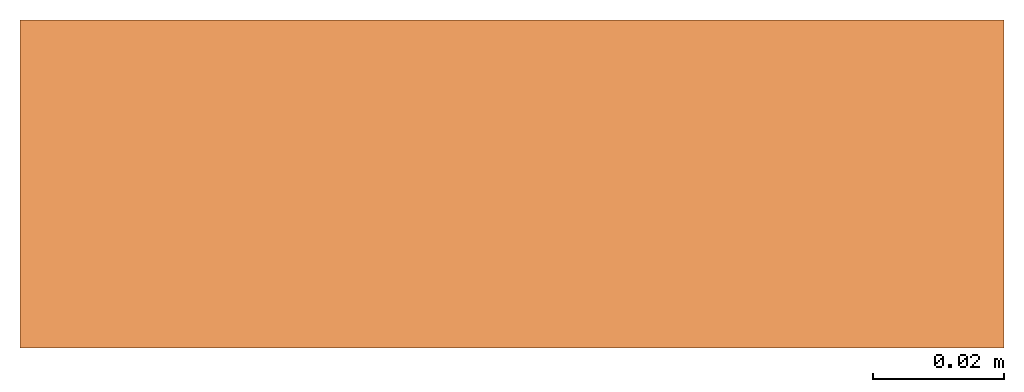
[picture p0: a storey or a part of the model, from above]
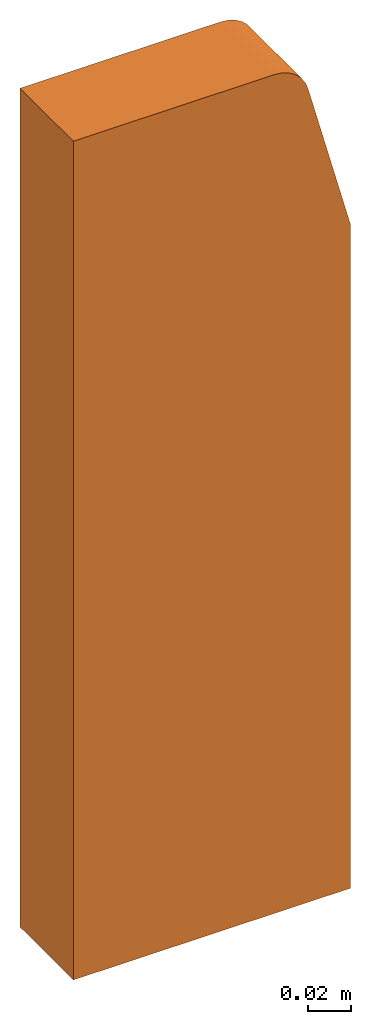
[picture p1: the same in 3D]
Properties of the parts of a building model (IFC2X3)

# File
Description: ViewDefinition [CoordinationView]
File name: 4938 - Closing end cap.ifc
Time: 2013-09-12T12:38:10
Written by: Autodesk Revit 2013
Made in: 20120221_2030(x64)

# IfcProject, Project Number
LongName: Project Name; Phase: Project Status

# IfcSite, Default
RefLatitude: 42, 21, 30, 344238; RefLongitude: -71, -3, -35, -194702; RefElevation: 0 mm

# IfcBuilding
Pset_BuildingCommon - NumberOfStoreys: 2
Other - Project Number: Project Number; Client Name: Owner; Project Address: Enter address here; Project Name: Project Name; Project Status: Project Status; Project Issue Date: Issue Date

# IfcBuildingStorey (2)
Constraints - Elevation Base: 0
Graphics - Symbol at End 1 Default: no; Symbol: M_Level Head - Circle: M_Level Head - Circle; Line Pattern: Center; Color: 0; Symbol at End 2 Default: yes; Line Weight: 1
Identity Data - Structural: no; Building Story: yes
Dimensions - Computation Height: 0 mm
Name | LongName = Name | Elevation (mm) = Constraints, Elevation (mm)
T.O. Fnd. Wall | T.O. Fnd. Wall | -300
Level 1 | Level 1 | 0

# IfcBuildingElementProxy: 4938 - Closing end cap, Civil-Drainage-Channel-ACO-KerbDrain-HB305 - PART 1:4938 - Closing end cap:4938 - Closing end cap:255899
In: T.O. Fnd. Wall
Material: ACO Polymer Concrete.
Other - CreatedBy: www.aco.co.uk; Revision: 1
Green Building Properties - End Cap Recycled Material Content: 20% minimum; End Cap Recyclable: Fully recyclable; Access Cover/Frame Recycled Material Content: N/A; Channel Recyclable: N/A; Access Cover/Frame Recyclable: N/A; Channel Recycled Material Content: N/A
Dimensions - Void_Width: 150 mm; I/O Endcap Void depth: 6000 mm; Staright Void Depth: -355 mm; Void_Length: 50 mm; Volume: 3530990 mm3
Phasing - Phase Created: Phase 1
Constraints - Moves With Nearby Elements: no; Level: Level: Level 1
Pset_BuildingElementProxyCommon - Reference: 4938 - Closing end cap
Identity Data - URL: www.aco.co.uk; OmniClass Title: Rainwater Removal; Type Comments: ACO KerbDrain HB305 half batter closing end cap; Maintenance guidelines: http://www.aco.co.uk/download.php?id=120; Address: ACO Business Park, Hitchin Road, Shefford, Bedfordshire, United Kingdom SG17 5TE; Cost: 0; Telephone: +44 (0)1462 816666; Product brochure: http://www.aco.co.uk/download.php?id=120; E-mail Sales: customersupport@aco.co.uk; Assembly Description: Rain Water Drainage; Fax: +44 (0)1462 815895; Product Code: 4938; Installation guidelines: http://www.aco.co.uk/download.php?id=120; Model Description: Combined kerb and drainage system; Price: POA - contact ACO; Product Page URL: http://www.aco.co.uk/product_detail.php?id=3; OmniClass Number: 23.70.50.24; Assembly Code: D2040; E-mail Technical: technical@aco.co.uk; Manufacturer: ACO Technologies plc - ACO Water Management Division; Model: ACO KerbDrain HB305
Data - Product Standard: N/A; Hydraulic Performance: N/A; Invert Depth: N/A; Channel C.S.A: N/A; Installation - Concrete Grade: N/A; Drainage Slot Width: N/A; Concrete Surround Volume - Load Class A 15 - D 400 - Grass or Asphalt Pavement: N/A; Concrete Surround Volume - Load Class A 15 - D 400 - Concrete Pavement: N/A; ACO Hydraulic Design Software: N/A; Drainage Slot Intake area: N/A; Connection Pipe O.D: N/A; Product Weight: 7.4 Kg; Load Class: N/A; Product Dimensions: 50mm x 150mm x 480mm (LxWxH)
Construction - KDHB305 - Channel unit - 500mm: no; KDHB305 - Perforated centre stone: no; KDHB305 - Channel unit - 250mm: no; KDHB305 - Drainable centre stone: no; KDHB305 - RH drop kerb: no; KDHB305 - LH Inlet/Outlet end cap: no; KDHB305 - Blind unit: no; KDHB305 - Access Unit: no; KDHB305 - LH drop kerb: no; KDHB305 - Closing end cap: yes; KDHB305 - RH Inlet/outlet end cap: no; I/O Pipe: no; KDHB305 - Channel unit - 1000mm: no; KDHB305 - Centre stone: no; KDHB305 - Flush LH dropkerb: no; KDHB305 - Flush RH dropkerb: no
General - TagNumber: 0.000000; SerialNumber: 0.000000
Materials and Finishes - Connection Pipe Material Colour: N/A; Access Cover/Frame Material: N/A; Access Cover/Frame Finish: N/A; Connection Pipe Material: N/A; Access Cover/Frame Colour: N/A; Channel Colour: N/A; End Cap Colour: Grey; Channel Material: N/A; End Cap Material: Vienite® Synthetic Resin Concrete

# IfcOpeningElement: Recess (2)
In: Level 1
Dimensions - Perimeter: 29157.2 mm; Thickness: 400 mm; Area: 53016081 mm2; Volume: 21203769706 mm3
Structural - Structural: no; Enable Analytical Model: no
Constraints - Height Offset From Level: 0 mm; Level: Level: Level 1; Related to Mass: no; Room Bounding: yes
Phasing - Phase Created: Phase 1
Analytical Properties - Absorptance: 0.1; Roughness: 1
Graphics - Coarse Scale Fill Color: 0
Construction - Function: 0; Default Thickness: 400 mm

# IfcSlab: Floor:Generic Floor - 400mm, Floor:Generic Floor - 400mm:184025
In: Level 1
PredefinedType: FLOOR; Material: Default Floor 400 mm
Dimensions - Perimeter: 29157.2 mm; Thickness: 400 mm; Area: 53016081 mm2; Volume: 21203769706 mm3
Structural - Structural: no; Enable Analytical Model: no
Constraints - Height Offset From Level: 0 mm; Level: Level: Level 1; Related to Mass: no; Room Bounding: yes
Phasing - Phase Created: Phase 1
Pset_SlabCommon - Reference: Generic Floor - 400mm; IsExternal: no; LoadBearing: yes
Analytical Properties - Absorptance: 0.1; Roughness: 1
Graphics - Coarse Scale Fill Color: 0
Construction - Function: 0; Default Thickness: 400 mm
